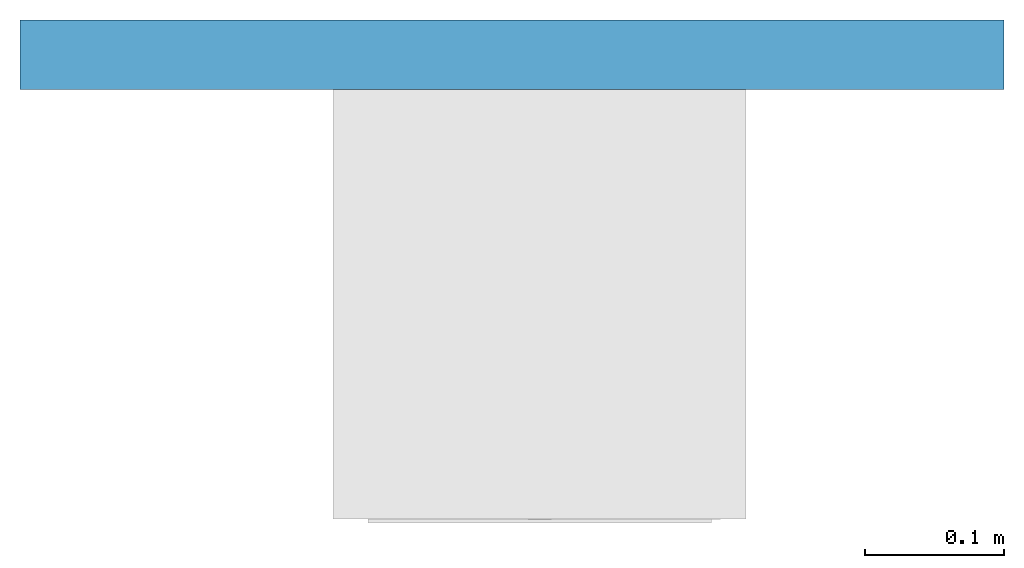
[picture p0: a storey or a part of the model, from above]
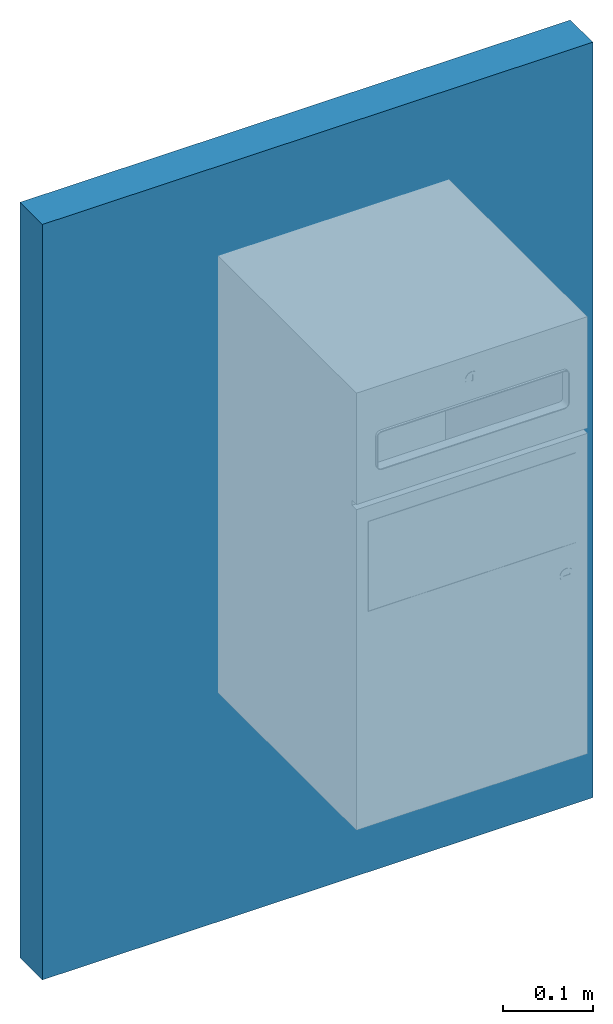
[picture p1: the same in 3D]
Properties of the parts of a building model (IFC2X3)

# File
Description: ViewDefinition [CoordinationView]
Time: 2018-06-15T12:40:51
Written by: The EXPRESS Data Manager Version 5.01.0100.02.64mod : 6 Jun 2012
Made in: 20140709_2115(x64) - Exporter 2014.0.2014.0709 - Default UI
Comment: STEP Physical File produced by: The EXPRESS Data Manager Version 5.01.0100.02.64mod : 6 Jun 2012 * Module: EDMstepFileFactory/EDMstandAlone * Creation date: Fri Jun 15 12:40:51 2018 * Host: BIM-HP * Database: C:\Users\dcole\AppData\Local\Temp\{E4AFAEB5-F307-4DB7-B7F7-B18DA0A2405B}\ifc * Database version: 5507 * Database creation date: Fri Jun 15 12:40:50 2018 * Schema: IFC2X3 * Model: DataRepository.ifc * Model creation date: Fri Jun 15 12:40:50 2018 * Header model: DataRepository.ifc_HeaderModel * Header model creation date: Fri Jun 15 12:40:50 2018 * EDMuser: sdai-user * EDMgroup: sdai-group * License ID and type: 5605 : Permanent license. Expiry date: * EDMstepFileFactory options: 020000

# IfcProject
LongName: P:\Fastrack\53721_DOLPHIN SOLUTIONS LIMITED\ADDITIONAL DRAWINGS 2018 BIM\IFC\DP4601.ifc

# IfcSite, Default
RefLatitude: 42, 24, 53, 508911; RefLongitude: -71, -15, -29, -58837; RefElevation: 0 mm

# IfcBuilding
Pset_BuildingCommon - NumberOfStoreys: 1

# IfcBuildingStorey, Level 1
LongName: Level 1; Elevation: 0 mm
Constraints - Elevation Base: Project Base Point; Elevation: 0 mm
Identity Data - Name: Level 1; Building Story: yes; Structural: no
Dimensions - Computation Height: 0 mm
Graphics - Line Weight: 1; Color: 0; Line Pattern: -3000010; Symbol at End 1 Default: no; Symbol at End 2 Default: yes

# IfcBuildingElementProxy: DP4601 Dolphin Towel Dispenser and Waste Bin Combination Unit, DP4601:DP4601 Dolphin Towel Dispenser and Waste Bin Combination Unit:108639
In: Level 1
Material: Stainless Steel
Phasing - Phase Created: New Construction
Constraints - Level: Level: Level 1; Host: Level : Level 1; Moves With Nearby Elements: no; Offset: 0 mm
Dimensions - Volume: 0.00855096 m3; Projection: 310mm; Width: 298mm; Height: 596mm; Capacity Paper Towels: 450 towels
Pset_ManufacturerTypeInformation - Manufacturer: Dolphin Solutions Ltd.
Pset_BuildingElementProxyCommon - Reference: DP4601 Dolphin Towel Dispenser and Waste Bin Combination Unit
General - Product Data: Superior quality and timeless design for prestigious washrooms. Easy-care 18/10 chrome nickel stainless steel combination unit. Satin finish, welded corners - no sharp edges. Towel dispenser for approx 450 paper towels. This unit is for mounting undera vanity counter. With removable mesh basket and self closing flap. Lockable. Mounted above the floor with a console for fixing to existing rear wall - console supplied as an optional extra. Also available in polished stainless steel or plastic powder coated to a colour of your choice.; Product Page Link: https://www.dolphinsolutions.co.uk/product/towel-dispenser-and-waste-bin-combination-unit-3
Identity Data - Manufacturer: Dolphin Solutions Ltd.; Address: Southpoint, Compass Park, Junction Road, Bodiam, TN32 5BS; Fax No.: +44 (0) 1424 205 200; Model: DP4601; Tel No.: +44 (0) 1424 202 224; URL: www.dolphinsolutions.co.uk; Assembly Description: Other Plumbing Fixtures; Email: info@dolphinsolutions.co.uk; Description: Towel dispenser and waste bin combination unit; Assembly Code: D2010900

# IfcWallStandardCase: Basic Wall:Wall 1, Basic Wall:Wall 1:3092
In: Level 1
Type - PredefinedType: STANDARD; Material: Default Wall 50 mm
Type - Analytical Properties - Absorptance: 0.1; Roughness: 1
Type - Graphics - Coarse Scale Fill Color: 8454143
Type - Construction - Width: 50 mm; Function: Exterior; Wrapping at Inserts: Do not wrap
Constraints - Related to Mass: no; Base Extension Distance: 0 mm; Room Bounding: yes; Location Line: Finish Face: Interior; Top Offset: 0 mm; Base is Attached: no; Base Offset: -313.075 mm; Top is Attached: no; Top Extension Distance: 0 mm; Unconnected Height: 1030.29 mm; Base Constraint: Level: Level 1
Dimensions - Length: 710 mm; Volume: 0.0365751 m3; Area: 0.731503 m2
Phasing - Phase Created: New Construction
Structural - Enable Analytical Model: no; Structural: no; Structural Usage: Non-bearing
Pset_WallCommon - Reference: Wall 1; LoadBearing: no; ExtendToStructure: no; IsExternal: yes
